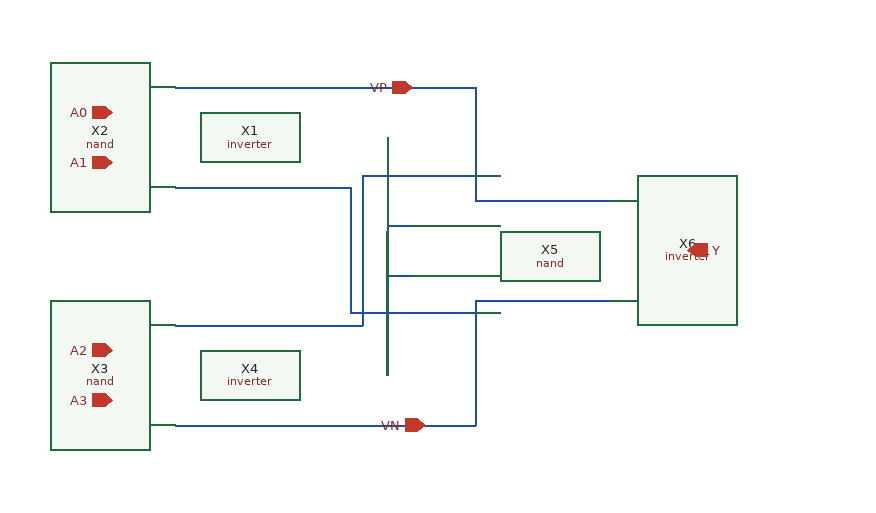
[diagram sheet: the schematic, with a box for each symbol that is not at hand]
v {xschem version=3.4.8RC file_version=1.3}
G {}
K {}
V {}
S {}
F {}
E {}
N 170 60 170 130 {lab=#net1}
N 170 130 190 130 {lab=#net1}
N 170 170 190 170 {lab=#net2}
N 170 170 170 250 {lab=#net2}
N -0 20 110 20 {lab=VP}
N 240 110 350 110 {lab=VP}
N 240 190 350 190 {lab=MUX0}
N 0 210 110 210 {lab=VP}
N 0 290 110 290 {lab=MUX0}
N -0 100 110 100 {lab=MUX0}
N 110 20 240 20 {lab=VP}
N 240 20 240 110 {lab=VP}
N 110 290 240 290 {lab=MUX0}
N 240 190 240 290 {lab=MUX0}
N 110 210 150 210 {lab=VP}
N 150 90 150 210 {lab=VP}
N 150 90 240 90 {lab=VP}
N 110 100 140 100 {lab=MUX0}
N 140 100 140 200 {lab=MUX0}
N 140 200 240 200 {lab=MUX0}
C {/home/madvlsi/Desktop/MP1/inverter.sym} 60 60 0 0 {name=X1}
C {/home/madvlsi/Desktop/MP1/nand.sym} -50 60 0 0 {name=X2}
C {/home/madvlsi/Desktop/MP1/nand.sym} -50 250 0 0 {name=X3}
C {/home/madvlsi/Desktop/MP1/inverter.sym} 60 250 0 0 {name=X4}
C {/home/madvlsi/Desktop/MP1/nand.sym} 190 150 0 0 {name=X5}
C {/home/madvlsi/Desktop/MP1/inverter.sym} 300 150 0 0 {name=X6}
C {ipin.sym} -50 40 0 0 {name=p3 lab=A0}
C {ipin.sym} -50 80 0 0 {name=p1 lab=A1}
C {ipin.sym} -50 230 0 0 {name=p2 lab=A2}
C {ipin.sym} -50 270 0 0 {name=p4 lab=A3}
C {opin.sym} 410 150 0 0 {name=p5 lab=Y}
C {iopin.sym} 190 20 3 0 {name=p6 lab=VP}
C {iopin.sym} 200 290 1 0 {name=p7 lab=VN}
